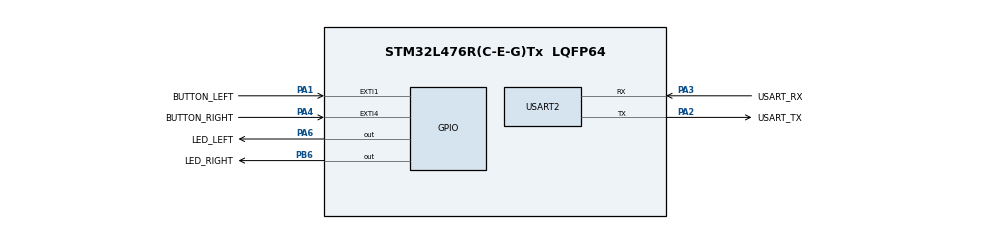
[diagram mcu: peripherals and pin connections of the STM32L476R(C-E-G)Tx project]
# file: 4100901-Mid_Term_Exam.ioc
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Mcu.Family=STM32L4
Mcu.Name=STM32L476R(C-E-G)Tx
Mcu.Package=LQFP64
NVIC.EXTI1_IRQn=true\:0\:0\:false\:false\:true\:true\:true\:true
NVIC.EXTI4_IRQn=true\:0\:0\:false\:false\:true\:true\:true\:true
NVIC.PriorityGroup=NVIC_PRIORITYGROUP_4
PA1.GPIO_Label=BUTTON_LEFT
PA1.Signal=GPXTI1
PA2.GPIO_Label=USART_TX
PA2.GPIO_Mode=GPIO_MODE_AF_PP
PA2.GPIO_PuPd=GPIO_NOPULL
PA2.GPIO_Speed=GPIO_SPEED_FREQ_VERY_HIGH
PA2.Mode=Asynchronous
PA2.Signal=USART2_TX
PA3.GPIO_Label=USART_RX
PA3.GPIO_Mode=GPIO_MODE_AF_PP
PA3.GPIO_PuPd=GPIO_NOPULL
PA3.GPIO_Speed=GPIO_SPEED_FREQ_VERY_HIGH
PA3.Mode=Asynchronous
PA3.Signal=USART2_RX
PA4.GPIO_Label=BUTTON_RIGHT
PA4.Signal=GPXTI4
PA6.GPIO_Label=LED_LEFT
PA6.Signal=GPIO_Output
PB6.GPIO_Label=LED_RIGHT
PB6.Signal=GPIO_Output
ProjectManager.HeapSize=0x200
ProjectManager.StackSize=0x400
ProjectManager.TargetToolchain=STM32CubeIDE
RCC.ADCFreq_Value=64000000
RCC.AHBFreq_Value=80000000
RCC.APB1Freq_Value=80000000
RCC.APB1TimFreq_Value=80000000
RCC.APB2Freq_Value=80000000
RCC.APB2TimFreq_Value=80000000
RCC.CortexFreq_Value=80000000
RCC.HCLKFreq_Value=80000000
RCC.HSE_VALUE=8000000
RCC.HSI_VALUE=16000000
RCC.LSE_VALUE=32768
RCC.MSI_VALUE=4000000
RCC.PLLN=10
RCC.PLLSourceVirtual=RCC_PLLSOURCE_HSI
RCC.PREFETCH_ENABLE=1
RCC.SYSCLKFreq_VALUE=80000000
RCC.SYSCLKSource=RCC_SYSCLKSOURCE_PLLCLK
RCC.USBFreq_Value=64000000
RCC.VCOOutputFreq_Value=160000000
USART2.VirtualMode-Asynchronous=VM_ASYNC
board=NUCLEO-L476RG

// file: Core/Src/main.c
/* USER CODE BEGIN Header */
/**
  **********
  * @file           : main.c
  * @brief          : Main program body
  **********
  * @attention
  *
  * Copyright (c) 2024 STMicroelectronics.
  * All rights reserved.
  *
  * This software is licensed under terms that can be found in the LICENSE file
  * in the root directory of this software component.
  * If no LICENSE file comes with this software, it is provided AS-IS.
  *
  **********
  */
/* USER CODE END Header */
#include "main.h"

UART_HandleTypeDef huart2;

/* USER CODE BEGIN PV */
uint8_t left_pressed = 0;
uint8_t right_pressed = 0;

uint8_t left_press_count = 0;
uint32_t last_left_press_time = 0;

uint8_t right_press_count = 0;
uint32_t last_right_press_time = 0;
/* USER CODE END PV */

void SystemClock_Config(void);
static void MX_GPIO_Init(void);
static void MX_USART2_UART_Init(void);

/* USER CODE BEGIN 0 */
void HAL_GPIO_EXTI_Callback(uint16_t GPIO_Pin) {
    if (GPIO_Pin == BUTTON_LEFT_Pin) {
        uint32_t current_time = HAL_GetTick();

        // Check if the last left button press was within 500ms
        if (current_time - last_left_press_time < 500) {
            left_press_count++;
        } else {
            left_press_count = 1;  // Reset count if too much time has passed
        }

        last_left_press_time = current_time;
        left_pressed = 1;
        HAL_UART_Transmit(&huart2, (uint8_t *)"left_active\r\n", 13, 10);

    } else if (GPIO_Pin == BUTTON_RIGHT_Pin) {
        uint32_t current_time = HAL_GetTick();

        // Check if the last right button press was within 500ms
        if (current_time - last_right_press_time < 500) {
            right_press_count++;
        } else {
            right_press_count = 1;  // Reset count if too much time has passed
        }

        last_right_press_time = current_time;
        right_pressed = 1;
        HAL_UART_Transmit(&huart2, (uint8_t *)"right_active\r\n", 14, 10);
    }
}

/* USER CODE END 0 */

int main(void) {

  /* MCU Configuration--------------------------------------------------------*/

  /* Reset of all peripherals, Initializes the Flash interface and the Systick. */
  HAL_Init();

  /* Configure the system clock */
  SystemClock_Config();

  /* Initialize all configured peripherals */
  MX_GPIO_Init();
  MX_USART2_UART_Init();

  /* Infinite loop */
  /* USER CODE BEGIN WHILE */
  while (1) {
      if (left_pressed != 0) {
          left_pressed = 0;  // Reset left button state at the start of the blink sequence

          if (left_press_count >= 2) {
              // Infinite blink for left LED
              while (1) {
                  HAL_GPIO_TogglePin(LED_LEFT_GPIO_Port, LED_LEFT_Pin);
                  HAL_Delay(250);
              }
          } else {
              // Blink left LED 3 times
              for (uint8_t i = 0; i < 6; i++) {
                  HAL_GPIO_TogglePin(LED_LEFT_GPIO_Port, LED_LEFT_Pin);
                  HAL_Delay(250);
              }
              HAL_GPIO_WritePin(LED_LEFT_GPIO_Port, LED_LEFT_Pin, 1);
          }
      }

      if (right_pressed != 0) {
          right_pressed = 0;  // Reset right button state at the start of the blink sequence

          if (right_press_count >= 2) {
              // Infinite blink for right LED
              while (1) {
                  HAL_GPIO_TogglePin(LED_RIGHT_GPIO_Port, LED_RIGHT_Pin);
                  HAL_Delay(250);
              }
          } else {
              // Blink right LED 3 times
              for (uint8_t i = 0; i < 6; i++) {
                  HAL_GPIO_TogglePin(LED_RIGHT_GPIO_Port, LED_RIGHT_Pin);
                  HAL_Delay(250);
              }
              HAL_GPIO_WritePin(LED_RIGHT_GPIO_Port, LED_RIGHT_Pin, 1);
          }
      }
    /* USER CODE END WHILE */

  }
}

void SystemClock_Config(void) {
  RCC_OscInitTypeDef RCC_OscInitStruct = {0};
  RCC_ClkInitTypeDef RCC_ClkInitStruct = {0};

  /** Configure the main internal regulator output voltage
  */
  if (HAL_PWREx_ControlVoltageScaling(PWR_REGULATOR_VOLTAGE_SCALE1) != HAL_OK) {
    Error_Handler();
  }

  /** Initializes the RCC Oscillators according to the specified parameters
  * in the RCC_OscInitTypeDef structure.
  */
  RCC_OscInitStruct.OscillatorType = RCC_OSCILLATORTYPE_MSI;
  RCC_OscInitStruct.MSIState = RCC_MSI_ON;
  RCC_OscInitStruct.MSICalibrationValue = 0;
  RCC_OscInitStruct.MSIClockRange = RCC_MSIRANGE_6;
  RCC_OscInitStruct.PLL.PLLState = RCC_PLL_NONE;
  if (HAL_RCC_OscConfig(&RCC_OscInitStruct) != HAL_OK) {
    Error_Handler();
  }

  /** Initializes the CPU, AHB and APB buses clocks
  */
  RCC_ClkInitStruct.ClockType = RCC_CLOCKTYPE_HCLK|RCC_CLOCKTYPE_SYSCLK
                              |RCC_CLOCKTYPE_PCLK1|RCC_CLOCKTYPE_PCLK2;
  RCC_ClkInitStruct.SYSCLKSource = RCC_SYSCLKSOURCE_MSI;
  RCC_ClkInitStruct.AHBCLKDivider = RCC_SYSCLK_DIV1;
  RCC_ClkInitStruct.APB1CLKDivider = RCC_HCLK_DIV1;
  RCC_ClkInitStruct.APB2CLKDivider = RCC_HCLK_DIV1;

  if (HAL_RCC_ClockConfig(&RCC_ClkInitStruct, FLASH_LATENCY_0) != HAL_OK) {
    Error_Handler();
  }
}

static void MX_USART2_UART_Init(void) {

  huart2.Instance = USART2;
  huart2.Init.BaudRate = 115200;
  huart2.Init.WordLength = UART_WORDLENGTH_8B;
  huart2.Init.StopBits = UART_STOPBITS_1;
  huart2.Init.Parity = UART_PARITY_NONE;
  huart2.Init.Mode = UART_MODE_TX_RX;
  huart2.Init.HwFlowCtl = UART_HWCONTROL_NONE;
  huart2.Init.OverSampling = UART_OVERSAMPLING_16;
  huart2.Init.OneBitSampling = UART_ONE_BIT_SAMPLE_DISABLE;
  huart2.AdvancedInit.AdvFeatureInit = UART_ADVFEATURE_NO_INIT;
  if (HAL_UART_Init(&huart2) != HAL_OK) {
    Error_Handler();
  }
}

static void MX_GPIO_Init(void) {
  GPIO_InitTypeDef GPIO_InitStruct = {0};

  /* GPIO Ports Clock Enable */
  __HAL_RCC_GPIOA_CLK_ENABLE();
  __HAL_RCC_GPIOB_CLK_ENABLE();

  /*Configure GPIO pin Output Level */
  HAL_GPIO_WritePin(LED_LEFT_GPIO_Port, LED_LEFT_Pin, GPIO_PIN_SET);

  /*Configure GPIO pin Output Level */
  HAL_GPIO_WritePin(LED_RIGHT_GPIO_Port, LED_RIGHT_Pin, GPIO_PIN_SET);

  /*Configure GPIO pins : BUTTON_LEFT_Pin BUTTON_RIGHT_Pin */
  GPIO_InitStruct.Pin = BUTTON_LEFT_Pin|BUTTON_RIGHT_Pin;
  GPIO_InitStruct.Mode = GPIO_MODE_IT_RISING;
  GPIO_InitStruct.Pull = GPIO_NOPULL;
  HAL_GPIO_Init(GPIOA, &GPIO_InitStruct);

  /*Configure GPIO pin : LED_LEFT_Pin */
  GPIO_InitStruct.Pin = LED_LEFT_Pin;
  GPIO_InitStruct.Mode = GPIO_MODE_OUTPUT_PP;
  GPIO_InitStruct.Pull = GPIO_NOPULL;
  GPIO_InitStruct.Speed = GPIO_SPEED_FREQ_LOW;
  HAL_GPIO_Init(LED_LEFT_GPIO_Port, &GPIO_InitStruct);

  /*Configure GPIO pin : LED_RIGHT_Pin */
  GPIO_InitStruct.Pin = LED_RIGHT_Pin;
  GPIO_InitStruct.Mode = GPIO_MODE_OUTPUT_PP;
  GPIO_InitStruct.Pull = GPIO_NOPULL;
  GPIO_InitStruct.Speed = GPIO_SPEED_FREQ_LOW;
  HAL_GPIO_Init(LED_RIGHT_GPIO_Port, &GPIO_InitStruct);

  /* EXTI interrupt init*/
  HAL_NVIC_SetPriority(EXTI1_IRQn, 0, 0);
  HAL_NVIC_EnableIRQ(EXTI1_IRQn);

  HAL_NVIC_SetPriority(EXTI4_IRQn, 0, 0);
  HAL_NVIC_EnableIRQ(EXTI4_IRQn);

}

void Error_Handler(void) {
  __disable_irq();
  while (1) {
  }
}
